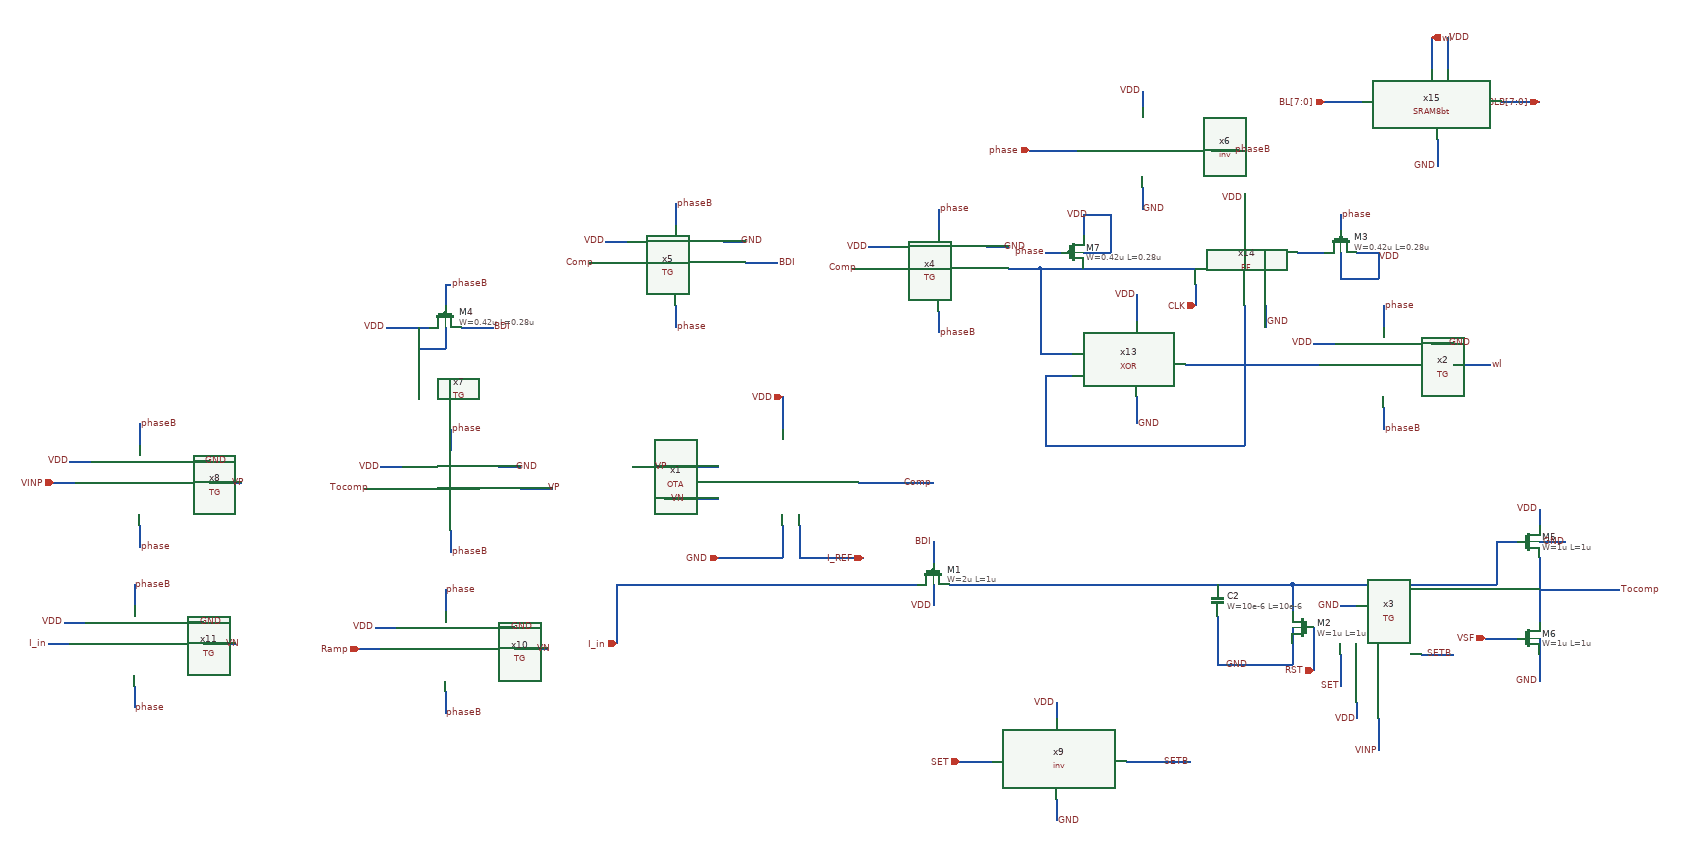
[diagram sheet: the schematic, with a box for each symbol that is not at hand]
v {xschem version=3.4.7 file_version=1.2}
G {}
K {}
V {}
S {}
E {}
N 690 -90 830 -90 {lab=Comp}
N 270 -120 430 -120 {lab=VP}
N 330 -60 430 -60 {lab=VN}
N 580 -10 580 50 {lab=I_REF}
N 550 -10 550 50 {lab=GND}
N 550 -250 550 -190 {lab=VDD}
N 830 20 830 60 {lab=BDI}
N 330 100 800 100 {lab=I_in}
N 240 100 330 100 {lab=I_in}
N 240 100 240 210 {lab=I_in}
N 580 50 700 50 {lab=I_REF}
N 430 50 550 50 {lab=GND}
N 830 100 830 140 {lab=VDD}
N 1250 100 1360 100 {lab=#net1}
N 1360 160 1360 240 {lab=GND}
N 1360 100 1500 100 {lab=#net1}
N 1500 100 1500 150 {lab=#net1}
N 1500 180 1500 210 {lab=GND}
N 1500 210 1500 250 {lab=GND}
N 1360 250 1500 250 {lab=GND}
N 1360 240 1360 250 {lab=GND}
N 1500 100 1700 100 {lab=#net1}
N 1700 100 1880 100 {lab=#net1}
N 1660 350 1660 410 {lab=VINP}
N 1540 180 1540 260 {lab=RST}
N 1170 100 1250 100 {lab=#net1}
N 880 430 940 430 {lab=SET}
N 1220 430 1310 430 {lab=SETB}
N 1590 230 1590 290 {lab=SET}
N 1740 230 1800 230 {lab=SETB}
N 1590 140 1620 140 {lab=GND}
N 1620 320 1620 350 {lab=VDD}
N 1960 50 1960 170 {lab=Tocomp}
N 1880 20 1880 100 {lab=#net1}
N 1860 200 1920 200 {lab=VSF}
N 1960 230 1960 280 {lab=GND}
N 1960 200 1960 230 {lab=GND}
N 1960 -40 1960 -10 {lab=VDD}
N 1960 110 2110 110 {lab=Tocomp}
N 1960 20 2010 20 {lab=GND}
N 1880 20 1920 20 {lab=#net1}
N 1790 -920 1790 -860 {lab=VDD}
N 1760 -920 1760 -860 {lab=wl}
N 1560 -800 1630 -800 {lab=BL[7:0]}
N 1890 -800 1960 -800 {lab=BLB[7:0]}
N 1770 -730 1770 -680 {lab=GND}
N 970 -490 1030 -490 {lab=#net2}
N 840 -600 840 -560 {lab=phase}
N 930 -530 970 -530 {lab=GND}
N 710 -530 750 -530 {lab=VDD}
N 680 -490 720 -490 {lab=Comp}
N 840 -410 840 -370 {lab=phaseB}
N 480 -500 540 -500 {lab=BDI}
N 350 -610 350 -570 {lab=phaseB}
N 440 -540 480 -540 {lab=GND}
N 220 -540 260 -540 {lab=VDD}
N 190 -500 230 -500 {lab=Comp}
N 350 -420 350 -380 {lab=phase}
N 1010 -710 1100 -710 {lab=phase}
N 1350 -710 1400 -710 {lab=phaseB}
N 1220 -820 1220 -790 {lab=VDD}
N 1220 -640 1220 -600 {lab=GND}
N 60 -80 120 -80 {lab=VP}
N -70 -190 -70 -150 {lab=phase}
N 20 -120 60 -120 {lab=GND}
N -200 -120 -160 -120 {lab=VDD}
N -230 -80 -190 -80 {lab=Tocomp}
N -70 0 -70 40 {lab=phaseB}
N -520 -90 -460 -90 {lab=VP}
N -650 -200 -650 -160 {lab=phaseB}
N -560 -130 -520 -130 {lab=GND}
N -780 -130 -740 -130 {lab=VDD}
N -810 -90 -770 -90 {lab=VINP}
N -650 -10 -650 30 {lab=phase}
N 1060 320 1060 350 {lab=VDD}
N 1060 500 1060 540 {lab=GND}
N 1190 430 1220 430 {lab=SETB}
N 50 220 110 220 {lab=VN}
N -80 110 -80 150 {lab=phase}
N 10 180 50 180 {lab=GND}
N -210 180 -170 180 {lab=VDD}
N -240 220 -200 220 {lab=Ramp}
N -80 300 -80 340 {lab=phaseB}
N -530 210 -470 210 {lab=VN}
N -660 100 -660 140 {lab=phaseB}
N -570 170 -530 170 {lab=GND}
N -790 170 -750 170 {lab=VDD}
N -820 210 -780 210 {lab=I_in}
N -660 290 -660 330 {lab=phase}
N 860 100 920 100 {lab=#net1}
N 1030 -490 1070 -490 {lab=#net2}
N 1210 -440 1210 -390 {lab=VDD}
N 1210 -250 1210 -200 {lab=GND}
N 1300 -310 1370 -310 {lab=#net3}
N 1030 -330 1090 -330 {lab=#net2}
N 1030 -490 1030 -330 {lab=#net2}
N 1070 -490 1320 -490 {lab=#net2}
N 1320 -460 1320 -420 {lab=CLK}
N 1410 -630 1410 -590 {lab=VDD}
N 1450 -420 1450 -380 {lab=GND}
N 1410 -420 1410 -380 {lab=#net4}
N 1040 -290 1040 -160 {lab=#net4}
N 1040 -290 1090 -290 {lab=#net4}
N 1510 -520 1560 -520 {lab=#net5}
N -80 -460 -70 -460 {lab=phaseB}
N -80 -460 -80 -420 {lab=phaseB}
N -50 -380 10 -380 {lab=BDI}
N -190 -380 -110 -380 {lab=VDD}
N -80 -380 -80 -340 {lab=VDD}
N -130 -340 -80 -340 {lab=VDD}
N -130 -380 -130 -340 {lab=VDD}
N 920 100 1170 100 {lab=#net1}
N 1410 -380 1410 -160 {lab=#net4}
N 1040 -160 1410 -160 {lab=#net4}
N 1590 -520 1590 -470 {lab=VDD}
N 1590 -470 1660 -470 {lab=VDD}
N 1620 -520 1650 -520 {lab=VDD}
N 1650 -520 1660 -520 {lab=VDD}
N 1660 -520 1660 -470 {lab=VDD}
N 1590 -590 1590 -560 {lab=phase}
N 1110 -520 1160 -520 {lab=VDD}
N 1160 -590 1160 -520 {lab=VDD}
N 1110 -580 1110 -550 {lab=VDD}
N 1110 -590 1110 -580 {lab=VDD}
N 1110 -590 1160 -590 {lab=VDD}
N 1040 -520 1070 -520 {lab=phase}
N 1670 -420 1670 -380 {lab=phase}
N 1760 -350 1800 -350 {lab=GND}
N 1540 -350 1580 -350 {lab=VDD}
N 1510 -310 1550 -310 {lab=#net3}
N 1670 -230 1670 -190 {lab=phaseB}
N 1800 -310 1870 -310 {lab=wl}
N 1370 -310 1510 -310 {lab=#net3}
C {pixel/OTA.sym} 550 -80 0 0 {name=x1}
C {symbols/pfet_03v3.sym} 830 80 1 0 {name=M1
L=1u
W=2u
nf=1
m=1
ad="'int((nf+1)/2) * W/nf * 0.18u'"
pd="'2*int((nf+1)/2) * (W/nf + 0.18u)'"
as="'int((nf+2)/2) * W/nf * 0.18u'"
ps="'2*int((nf+2)/2) * (W/nf + 0.18u)'"
nrd="'0.18u / W'" nrs="'0.18u / W'"
sa=0 sb=0 sd=0
model=pfet_03v3
spiceprefix=X
}
C {iopin.sym} -810 -90 1 0 {name=p1 lab=VINP}
C {iopin.sym} 240 210 0 0 {name=p2 lab=I_in}
C {iopin.sym} 700 50 0 0 {name=p3 lab=I_REF}
C {iopin.sym} 430 50 2 0 {name=p4 lab=GND}
C {iopin.sym} 550 -250 0 0 {name=p5 lab=VDD}
C {symbols/nfet_03v3.sym} 1520 180 0 1 {name=M2
L=1u
W=1u
nf=1
m=1
ad="'int((nf+1)/2) * W/nf * 0.18u'"
pd="'2*int((nf+1)/2) * (W/nf + 0.18u)'"
as="'int((nf+2)/2) * W/nf * 0.18u'"
ps="'2*int((nf+2)/2) * (W/nf + 0.18u)'"
nrd="'0.18u / W'" nrs="'0.18u / W'"
sa=0 sb=0 sd=0
model=nfet_03v3
spiceprefix=X
}
C {lab_pin.sym} 1420 250 3 0 {name=p6 sig_type=std_logic lab=GND}
C {lab_pin.sym} 1660 410 3 0 {name=p7 sig_type=std_logic lab=VINP}
C {iopin.sym} 1540 260 1 0 {name=p8 lab=RST}
C {iopin.sym} 880 430 2 0 {name=p9 lab=SET
}
C {lab_pin.sym} 1310 430 3 0 {name=p10 sig_type=std_logic lab=SETB}
C {pixel/TG.sym} 1650 240 3 0 {name=x3}
C {lab_pin.sym} 1590 290 3 0 {name=p12 sig_type=std_logic lab=SET}
C {lab_pin.sym} 1590 140 3 0 {name=p13 sig_type=std_logic lab=GND}
C {lab_pin.sym} 1620 350 3 0 {name=p16 sig_type=std_logic lab=VDD}
C {lab_pin.sym} 1800 230 3 0 {name=p17 sig_type=std_logic lab=SETB}
C {symbols/nfet_03v3.sym} 1940 20 0 0 {name=M5
L=1u
W=1u
nf=1
m=1
ad="'int((nf+1)/2) * W/nf * 0.18u'"
pd="'2*int((nf+1)/2) * (W/nf + 0.18u)'"
as="'int((nf+2)/2) * W/nf * 0.18u'"
ps="'2*int((nf+2)/2) * (W/nf + 0.18u)'"
nrd="'0.18u / W'" nrs="'0.18u / W'"
sa=0 sb=0 sd=0
model=nfet_03v3
spiceprefix=X
}
C {symbols/nfet_03v3.sym} 1940 200 0 0 {name=M6
L=1u
W=1u
nf=1
m=1
ad="'int((nf+1)/2) * W/nf * 0.18u'"
pd="'2*int((nf+1)/2) * (W/nf + 0.18u)'"
as="'int((nf+2)/2) * W/nf * 0.18u'"
ps="'2*int((nf+2)/2) * (W/nf + 0.18u)'"
nrd="'0.18u / W'" nrs="'0.18u / W'"
sa=0 sb=0 sd=0
model=nfet_03v3
spiceprefix=X
}
C {iopin.sym} 1860 200 1 0 {name=p21 lab=VSF}
C {lab_pin.sym} 1960 280 3 0 {name=p22 sig_type=std_logic lab=GND}
C {lab_pin.sym} 1960 -40 1 0 {name=p23 sig_type=std_logic lab=VDD}
C {lab_pin.sym} 2010 20 3 0 {name=p24 sig_type=std_logic lab=GND}
C {lab_pin.sym} 830 140 3 0 {name=p26 sig_type=std_logic lab=VDD}
C {lab_pin.sym} 1790 -920 0 1 {name=p27 sig_type=std_logic lab=VDD}
C {iopin.sym} 1760 -920 0 1 {name=p28 lab=wl}
C {lab_pin.sym} 1770 -680 0 0 {name=p29 sig_type=std_logic lab=GND}
C {iopin.sym} 1560 -800 2 0 {name=p30 lab=BL[7:0]}
C {iopin.sym} 1960 -800 0 0 {name=p31 lab=BLB[7:0]}
C {lab_wire.sym} 830 -90 0 0 {name=p32 sig_type=std_logic lab=Comp}
C {pixel/TG.sym} 830 -500 0 0 {name=x4}
C {lab_pin.sym} 710 -530 0 0 {name=p34 sig_type=std_logic lab=VDD}
C {lab_wire.sym} 690 -490 0 0 {name=p35 sig_type=std_logic lab=Comp}
C {pixel/TG.sym} 340 -510 0 0 {name=x5}
C {lab_pin.sym} 470 -540 2 0 {name=p37 sig_type=std_logic lab=GND}
C {lab_pin.sym} 220 -540 0 0 {name=p38 sig_type=std_logic lab=VDD}
C {lab_wire.sym} 200 -500 0 0 {name=p39 sig_type=std_logic lab=Comp}
C {lab_wire.sym} 830 20 0 0 {name=p36 sig_type=std_logic lab=BDI}
C {lab_wire.sym} 540 -500 2 0 {name=p40 sig_type=std_logic lab=BDI}
C {iopin.sym} 1010 -710 2 0 {name=p41 lab=phase}
C {pixel/inv.sym} 1200 -710 0 0 {name=x6}
C {lab_pin.sym} 1220 -820 0 0 {name=p42 sig_type=std_logic lab=VDD}
C {lab_pin.sym} 1220 -600 2 0 {name=p43 sig_type=std_logic lab=GND}
C {lab_wire.sym} 1390 -710 2 0 {name=p44 sig_type=std_logic lab=phaseB}
C {lab_wire.sym} 840 -370 2 0 {name=p45 sig_type=std_logic lab=phaseB}
C {lab_pin.sym} 960 -530 2 0 {name=p46 sig_type=std_logic lab=GND}
C {lab_pin.sym} 840 -600 2 0 {name=p47 sig_type=std_logic lab=phase}
C {lab_wire.sym} 350 -610 2 0 {name=p48 sig_type=std_logic lab=phaseB}
C {lab_pin.sym} 350 -380 2 0 {name=p49 sig_type=std_logic lab=phase}
C {pixel/TG.sym} -80 -90 0 0 {name=x7}
C {lab_pin.sym} -200 -120 0 0 {name=p52 sig_type=std_logic lab=VDD}
C {pixel/TG.sym} -660 -100 0 0 {name=x8}
C {lab_pin.sym} -530 -130 2 0 {name=p54 sig_type=std_logic lab=GND}
C {lab_pin.sym} -780 -130 0 0 {name=p55 sig_type=std_logic lab=VDD}
C {lab_wire.sym} -70 40 2 0 {name=p58 sig_type=std_logic lab=phaseB}
C {lab_pin.sym} 50 -120 2 0 {name=p59 sig_type=std_logic lab=GND}
C {lab_pin.sym} -70 -190 2 0 {name=p60 sig_type=std_logic lab=phase}
C {lab_wire.sym} -650 -200 2 0 {name=p61 sig_type=std_logic lab=phaseB}
C {lab_pin.sym} -650 30 2 0 {name=p62 sig_type=std_logic lab=phase}
C {pixel/inv.sym} 1040 430 0 0 {name=x9}
C {lab_pin.sym} 1060 320 0 0 {name=p11 sig_type=std_logic lab=VDD}
C {lab_pin.sym} 1060 540 2 0 {name=p15 sig_type=std_logic lab=GND}
C {lab_wire.sym} 110 -80 2 0 {name=p50 sig_type=std_logic lab=VP}
C {lab_wire.sym} -480 -90 2 0 {name=p53 sig_type=std_logic lab=VP}
C {lab_pin.sym} 2110 110 2 0 {name=p56 sig_type=std_logic lab=Tocomp
}
C {lab_pin.sym} -220 -80 0 0 {name=p57 sig_type=std_logic lab=Tocomp
}
C {lab_wire.sym} 310 -120 2 0 {name=p63 sig_type=std_logic lab=VP}
C {pixel/TG.sym} -90 210 0 0 {name=x10}
C {lab_pin.sym} -210 180 0 0 {name=p66 sig_type=std_logic lab=VDD}
C {pixel/TG.sym} -670 200 0 0 {name=x11}
C {lab_pin.sym} -540 170 2 0 {name=p67 sig_type=std_logic lab=GND}
C {lab_pin.sym} -790 170 0 0 {name=p68 sig_type=std_logic lab=VDD}
C {lab_wire.sym} -80 340 2 0 {name=p69 sig_type=std_logic lab=phaseB}
C {lab_pin.sym} 40 180 2 0 {name=p70 sig_type=std_logic lab=GND}
C {lab_pin.sym} -80 110 2 0 {name=p71 sig_type=std_logic lab=phase}
C {lab_wire.sym} -660 100 2 0 {name=p72 sig_type=std_logic lab=phaseB}
C {lab_pin.sym} -660 330 2 0 {name=p73 sig_type=std_logic lab=phase}
C {lab_wire.sym} -490 210 2 0 {name=p75 sig_type=std_logic lab=VN
}
C {lab_pin.sym} -820 210 0 0 {name=p64 sig_type=std_logic lab=I_in}
C {lab_wire.sym} 340 -60 2 0 {name=p77 sig_type=std_logic lab=VN
}
C {lab_wire.sym} 90 220 2 0 {name=p74 sig_type=std_logic lab=VN
}
C {iopin.sym} -240 220 2 0 {name=p76 lab=Ramp}
C {symbols/cap_mim_2f0fF.sym} 1360 130 0 0 {name=C2
W=10e-6
L=10e-6
model=cap_mim_2f0fF
spiceprefix=X
m=1}
C {pixel/XOR.sym} 1190 -310 0 0 {name=x13}
C {lab_pin.sym} 1210 -440 0 0 {name=p80 sig_type=std_logic lab=VDD}
C {lab_pin.sym} 1210 -200 2 0 {name=p81 sig_type=std_logic lab=GND}
C {pixel/FF.sym} 1410 -490 0 0 {name=x14}
C {lab_pin.sym} 1450 -390 2 0 {name=p82 sig_type=std_logic lab=GND}
C {lab_pin.sym} 1410 -620 0 0 {name=p83 sig_type=std_logic lab=VDD}
C {iopin.sym} 1320 -420 0 0 {name=p86 lab=CLK}
C {pixel/SRAM8bt.sym} 1740 -800 0 0 {name=x15}
C {symbols/pfet_03v3.sym} -80 -400 1 0 {name=M4
L=0.28u
W=0.42u
nf=1
m=1
ad="'int((nf+1)/2) * W/nf * 0.18u'"
pd="'2*int((nf+1)/2) * (W/nf + 0.18u)'"
as="'int((nf+2)/2) * W/nf * 0.18u'"
ps="'2*int((nf+2)/2) * (W/nf + 0.18u)'"
nrd="'0.18u / W'" nrs="'0.18u / W'"
sa=0 sb=0 sd=0
model=pfet_03v3
spiceprefix=X
}
C {lab_wire.sym} -70 -460 2 0 {name=p90 sig_type=std_logic lab=phaseB}
C {lab_pin.sym} -190 -380 0 0 {name=p91 sig_type=std_logic lab=VDD}
C {lab_wire.sym} 10 -380 2 0 {name=p92 sig_type=std_logic lab=BDI}
C {lab_pin.sym} 1870 -310 2 0 {name=p14 sig_type=std_logic lab=wl}
C {symbols/pfet_03v3.sym} 1590 -540 1 0 {name=M3
L=0.28u
W=0.42u
nf=1
m=1
ad="'int((nf+1)/2) * W/nf * 0.18u'"
pd="'2*int((nf+1)/2) * (W/nf + 0.18u)'"
as="'int((nf+2)/2) * W/nf * 0.18u'"
ps="'2*int((nf+2)/2) * (W/nf + 0.18u)'"
nrd="'0.18u / W'" nrs="'0.18u / W'"
sa=0 sb=0 sd=0
model=pfet_03v3
spiceprefix=X
}
C {lab_pin.sym} 1660 -510 2 0 {name=p18 sig_type=std_logic lab=VDD}
C {lab_pin.sym} 1590 -590 2 0 {name=p19 sig_type=std_logic lab=phase}
C {symbols/pfet_03v3.sym} 1090 -520 0 0 {name=M7
L=0.28u
W=0.42u
nf=1
m=1
ad="'int((nf+1)/2) * W/nf * 0.18u'"
pd="'2*int((nf+1)/2) * (W/nf + 0.18u)'"
as="'int((nf+2)/2) * W/nf * 0.18u'"
ps="'2*int((nf+2)/2) * (W/nf + 0.18u)'"
nrd="'0.18u / W'" nrs="'0.18u / W'"
sa=0 sb=0 sd=0
model=pfet_03v3
spiceprefix=X
}
C {lab_pin.sym} 1120 -590 1 0 {name=p20 sig_type=std_logic lab=VDD}
C {lab_pin.sym} 1040 -520 1 0 {name=p25 sig_type=std_logic lab=phase}
C {pixel/TG.sym} 1660 -320 0 0 {name=x2}
C {lab_pin.sym} 1540 -350 0 0 {name=p33 sig_type=std_logic lab=VDD}
C {lab_wire.sym} 1670 -190 2 0 {name=p65 sig_type=std_logic lab=phaseB}
C {lab_pin.sym} 1790 -350 2 0 {name=p78 sig_type=std_logic lab=GND}
C {lab_pin.sym} 1670 -420 2 0 {name=p79 sig_type=std_logic lab=phase}
